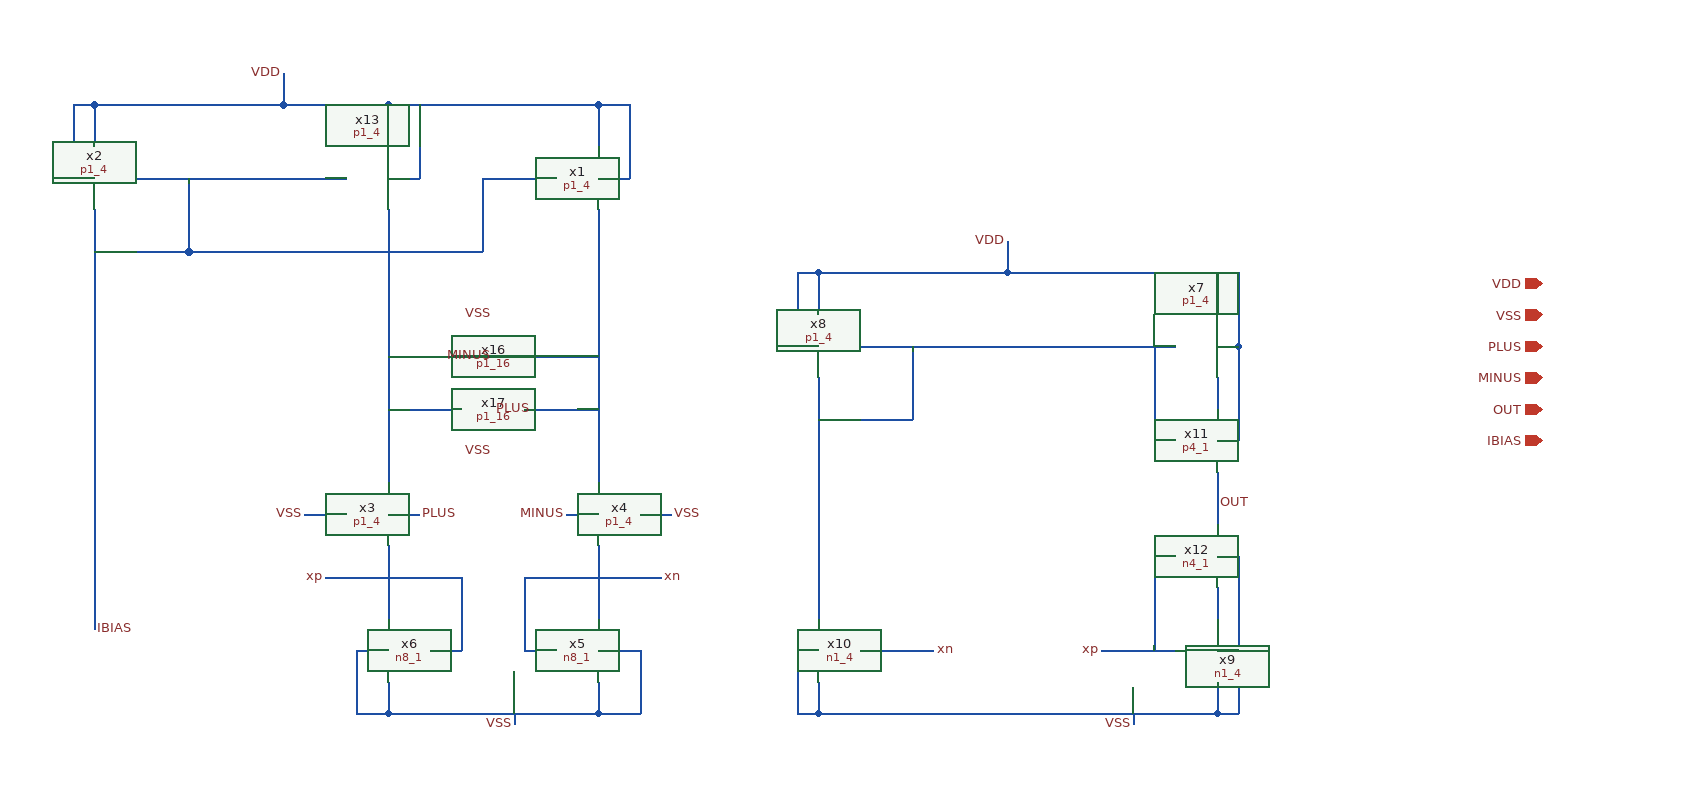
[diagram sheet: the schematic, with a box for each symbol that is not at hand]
v {xschem version=2.9.9 file_version=1.2 }
G {}
K {}
V {}
S {}
E {}
N 110 -650 210 -650 { lab=IBIAS}
N 70 -720 250 -720 { lab=VDD}
N 70 -720 70 -680 { lab=VDD}
N 160 -650 160 -580 { lab=IBIAS}
N 70 -580 160 -580 { lab=IBIAS}
N 50 -650 70 -650 { lab=VDD}
N 50 -720 50 -650 { lab=VDD}
N 50 -720 70 -720 { lab=VDD}
N 70 -620 70 -570 { lab=IBIAS}
N 350 -300 350 -230 { lab=xp}
N 550 -300 550 -230 { lab=xn}
N 350 -170 350 -140 { lab=VSS}
N 350 -140 550 -140 { lab=VSS}
N 550 -170 550 -140 { lab=VSS}
N 70 -340 70 -220 { lab=IBIAS}
N 70 -350 70 -340 { lab=IBIAS}
N 270 -330 310 -330 { lab=VSS}
N 320 -200 350 -200 { lab=VSS}
N 320 -200 320 -140 { lab=VSS}
N 550 -200 590 -200 { lab=VSS}
N 590 -200 590 -140 { lab=VSS}
N 550 -140 590 -140 { lab=VSS}
N 550 -270 610 -270 { lab=xn}
N 590 -330 620 -330 { lab=VSS}
N 320 -140 350 -140 { lab=VSS}
N 70 -570 70 -350 { lab=IBIAS}
N 250 -750 250 -720 { lab=VDD}
N 470 -140 470 -130 { lab=VSS}
N 350 -270 420 -270 { lab=xp}
N 420 -270 420 -200 { lab=xp}
N 390 -200 420 -200 { lab=xp}
N 480 -200 510 -200 { lab=xn}
N 480 -270 480 -200 { lab=xn}
N 480 -270 550 -270 { lab=xn}
N 290 -270 350 -270 { lab=xp}
N 800 -490 900 -490 { lab=#net1}
N 1140 -560 1140 -520 { lab=VDD}
N 760 -560 940 -560 { lab=VDD}
N 760 -560 760 -520 { lab=VDD}
N 850 -490 850 -420 { lab=#net1}
N 760 -420 850 -420 { lab=#net1}
N 1140 -490 1160 -490 { lab=VDD}
N 1160 -560 1160 -490 { lab=VDD}
N 740 -490 760 -490 { lab=VDD}
N 740 -560 740 -490 { lab=VDD}
N 740 -560 760 -560 { lab=VDD}
N 760 -460 760 -410 { lab=#net1}
N 940 -560 1150 -560 { lab=VDD}
N 1140 -460 1140 -450 { lab=#net2}
N 940 -590 940 -560 { lab=VDD}
N 900 -490 1100 -490 { lab=#net1}
N 1140 -170 1140 -140 { lab=VSS}
N 1060 -140 1060 -130 { lab=VSS}
N 760 -410 760 -340 { lab=#net1}
N 760 -170 760 -140 { lab=VSS}
N 760 -140 1110 -140 { lab=VSS}
N 800 -200 870 -200 { lab=xn}
N 1030 -200 1100 -200 { lab=xp}
N 1110 -140 1140 -140 { lab=VSS}
N 740 -200 760 -200 { lab=VSS}
N 740 -200 740 -140 { lab=VSS}
N 740 -140 760 -140 { lab=VSS}
N 760 -340 760 -230 { lab=#net1}
N 1140 -450 1140 -430 { lab=#net2}
N 1140 -400 1160 -400 { lab=VDD}
N 1160 -490 1160 -400 { lab=VDD}
N 1080 -400 1100 -400 { lab=#net1}
N 1080 -490 1080 -400 { lab=#net1}
N 1080 -290 1100 -290 { lab=xp}
N 1080 -290 1080 -200 { lab=xp}
N 1140 -260 1140 -230 { lab=#net3}
N 350 -380 350 -360 { lab=#net4}
N 350 -550 350 -380 { lab=#net4}
N 210 -650 310 -650 { lab=IBIAS}
N 550 -620 550 -360 { lab=#net5}
N 350 -620 350 -550 { lab=#net4}
N 350 -720 350 -680 { lab=VDD}
N 250 -720 350 -720 { lab=VDD}
N 550 -720 550 -680 { lab=VDD}
N 350 -720 550 -720 { lab=VDD}
N 160 -580 440 -580 { lab=IBIAS}
N 440 -650 440 -580 { lab=IBIAS}
N 440 -650 510 -650 { lab=IBIAS}
N 350 -650 380 -650 { lab=VDD}
N 380 -720 380 -650 { lab=VDD}
N 550 -650 580 -650 { lab=VDD}
N 550 -720 580 -720 { lab=VDD}
N 580 -720 580 -650 { lab=VDD}
N 350 -330 380 -330 { lab=PLUS}
N 520 -330 550 -330 { lab=MINUS}
N 350 -430 420 -430 { lab=#net4}
N 350 -480 420 -480 { lab=#net4}
N 480 -480 550 -480 { lab=#net5}
N 480 -430 550 -430 { lab=#net5}
N 1150 -560 1160 -560 { lab=VDD}
N 1140 -330 1140 -320 { lab=OUT}
N 1140 -370 1140 -360 { lab=OUT}
N 1140 -290 1160 -290 { lab=VSS}
N 1160 -290 1160 -140 { lab=VSS}
N 1140 -140 1160 -140 { lab=VSS}
N 1140 -200 1160 -200 { lab=VSS}
N 1140 -360 1140 -330 { lab=OUT}
C {devices/lab_pin.sym} 270 -330 0 0 {name=l13 sig_type=std_logic lab=VSS}
C {devices/lab_pin.sym} 620 -330 2 0 {name=l14 sig_type=std_logic lab=VSS}
C {devices/lab_pin.sym} 70 -220 2 0 {name=l15 sig_type=std_logic lab=IBIAS}
C {devices/lab_pin.sym} 610 -270 2 0 {name=l16 sig_type=std_logic lab=xn}
C {devices/title.sym} 160 -40 0 0 {name=l6 author="LCI Team"}
C {devices/iopin.sym} 1450 -550 0 0 {name=p1 lab=VDD}
C {devices/iopin.sym} 1450 -520 0 0 {name=p2 lab=VSS}
C {devices/iopin.sym} 1450 -490 0 0 {name=p3 lab=PLUS}
C {devices/iopin.sym} 1450 -460 0 0 {name=p4 lab=MINUS}
C {devices/iopin.sym} 1450 -430 0 0 {name=p5 lab=OUT}
C {devices/iopin.sym} 1450 -400 0 0 {name=p6 lab=IBIAS}
C {devices/lab_pin.sym} 250 -750 1 0 {name=l3 sig_type=std_logic lab=VDD}
C {devices/lab_pin.sym} 470 -130 3 0 {name=l1 sig_type=std_logic lab=VSS}
C {ARRAY/p1_4.sym} 90 -650 2 0 {name=x2}
C {ARRAY/p1_4.sym} 330 -330 0 0 {name=x3}
C {ARRAY/p1_4.sym} 570 -330 2 0 {name=x4}
C {ARRAY/n8_1.sym} 530 -200 0 0 {name=x5}
C {ARRAY/n8_1.sym} 370 -200 2 0 {name=x6}
C {devices/lab_pin.sym} 290 -270 0 0 {name=l5 sig_type=std_logic lab=xp}
C {devices/lab_pin.sym} 940 -590 1 0 {name=l7 sig_type=std_logic lab=VDD}
C {ARRAY/p1_4.sym} 1120 -490 0 0 {name=x7}
C {ARRAY/p1_4.sym} 780 -490 2 0 {name=x8}
C {devices/lab_pin.sym} 870 -200 2 0 {name=l8 sig_type=std_logic lab=xn}
C {devices/lab_pin.sym} 1060 -130 3 0 {name=l9 sig_type=std_logic lab=VSS}
C {ARRAY/n1_4.sym} 1120 -200 0 0 {name=x9}
C {ARRAY/n1_4.sym} 780 -200 0 1 {name=x10}
C {devices/lab_pin.sym} 1030 -200 2 1 {name=l10 sig_type=std_logic lab=xp}
C {ARRAY/p4_1.sym} 1120 -400 0 0 {name=x11}
C {ARRAY/n4_1.sym} 1120 -290 0 0 {name=x12}
C {ARRAY/p1_4.sym} 530 -650 2 1 {name=x1}
C {ARRAY/p1_4.sym} 330 -650 2 1 {name=x13}
C {devices/lab_pin.sym} 1140 -340 2 0 {name=l17 sig_type=std_logic lab=OUT}
C {devices/lab_pin.sym} 380 -330 2 0 {name=l2 sig_type=std_logic lab=PLUS}
C {devices/lab_pin.sym} 520 -330 0 0 {name=l20 sig_type=std_logic lab=MINUS}
C {ARRAY/p1_16.sym} 450 -500 1 0 {name=x16}
C {ARRAY/p1_16.sym} 450 -410 3 0 {name=x17}
C {devices/lab_pin.sym} 450 -520 1 0 {name=l22 sig_type=std_logic lab=VSS}
C {devices/lab_pin.sym} 450 -390 3 0 {name=l23 sig_type=std_logic lab=VSS}
C {devices/lab_pin.sym} 450 -480 0 0 {name=l21 sig_type=std_logic lab=MINUS}
C {devices/lab_pin.sym} 450 -430 2 0 {name=l24 sig_type=std_logic lab=PLUS}
